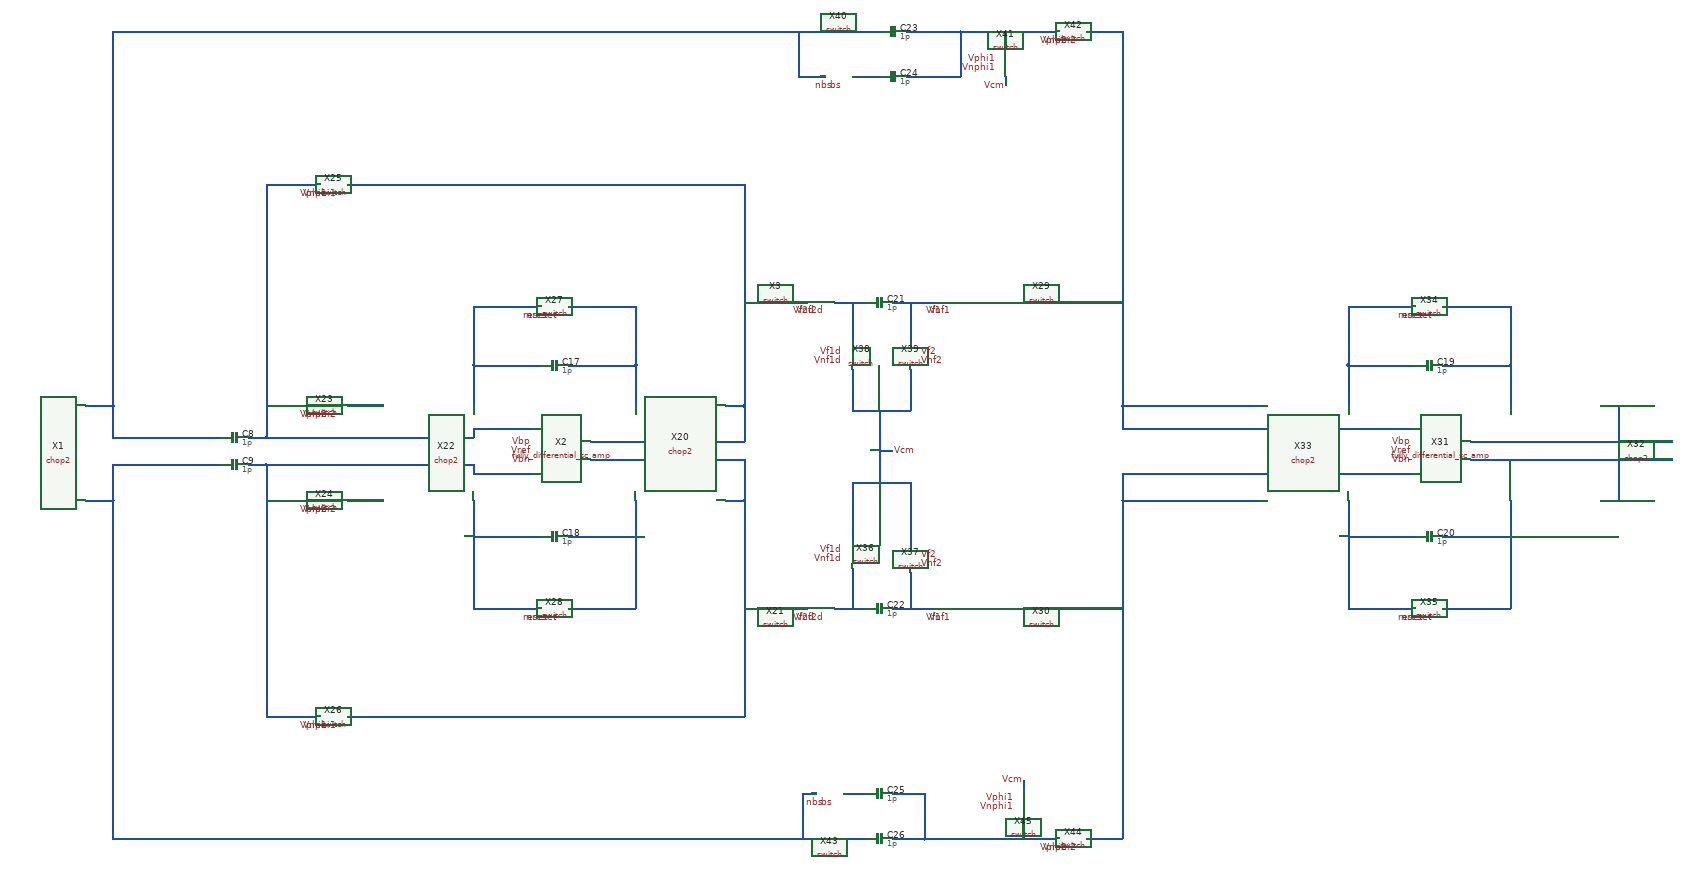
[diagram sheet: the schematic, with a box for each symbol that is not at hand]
v {xschem version=2.9.9 file_version=1.2 }
G {}
K {}
V {}
S {}
E {}
N 840 -1180 840 -620 { lab=#net1}
N 840 -560 840 -0 { lab=#net2}
N 840 -1180 960 -1180 { lab=#net1}
N 840 -690 960 -690 { lab=#net1}
N 1020 -690 1100 -690 { lab=#net3}
N 840 0 960 -0 { lab=#net2}
N 1300 -780 1450 -780 { lab=#net4}
N 1510 -780 1660 -780 { lab=#net5}
N 1660 -780 1660 -690 { lab=#net5}
N 1300 -400 1450 -400 { lab=#net6}
N 1510 -400 1660 -400 { lab=#net7}
N 1660 -480 1660 -420 { lab=#net7}
N 1300 -910 1450 -910 { lab=#net4}
N 1300 -910 1300 -780 { lab=#net4}
N 1510 -910 1660 -910 { lab=#net5}
N 1660 -910 1660 -780 { lab=#net5}
N 1510 -240 1660 -240 { lab=#net7}
N 1660 -420 1660 -240 { lab=#net7}
N 1300 -420 1300 -240 { lab=#net6}
N 1300 -240 1450 -240 { lab=#net6}
N 1300 -780 1300 -690 { lab=#net4}
N 1300 -480 1300 -420 { lab=#net6}
N 840 -480 960 -480 { lab=#net2}
N 1020 -480 1100 -480 { lab=#net8}
N 1860 -690 1900 -690 { lab=#net9}
N 1900 -1180 1900 -690 { lab=#net9}
N 1020 -1180 1900 -1180 { lab=#net9}
N 1020 -0 1900 -0 { lab=#net10}
N 1900 -480 1900 -0 { lab=#net10}
N 1860 -480 1900 -480 { lab=#net10}
N 3240 -780 3390 -780 { lab=#net11}
N 3450 -780 3600 -780 { lab=#net12}
N 3600 -780 3600 -690 { lab=#net12}
N 3240 -400 3390 -400 { lab=#net13}
N 3450 -400 3600 -400 { lab=#net14}
N 3600 -480 3600 -420 { lab=#net14}
N 3240 -910 3390 -910 { lab=#net11}
N 3240 -910 3240 -780 { lab=#net11}
N 3450 -910 3600 -910 { lab=#net12}
N 3600 -910 3600 -780 { lab=#net12}
N 3450 -240 3600 -240 { lab=#net14}
N 3600 -420 3600 -240 { lab=#net14}
N 3240 -420 3240 -240 { lab=#net13}
N 3240 -240 3390 -240 { lab=#net13}
N 3240 -780 3240 -690 { lab=#net11}
N 3240 -480 3240 -420 { lab=#net13}
N 500 270 2170 270 { lab=#net15}
N 2030 170 2060 170 { lab=#net15}
N 2030 170 2030 270 { lab=#net15}
N 2120 170 2170 170 { lab=#net16}
N 2230 170 2300 170 { lab=#net17}
N 2300 170 2300 270 { lab=#net17}
N 2230 270 2300 270 { lab=#net17}
N 2300 270 2600 270 { lab=#net17}
N 2520 220 2520 270 { lab=#net17}
N 1900 -240 2040 -240 { lab=#net10}
N 2100 -240 2170 -240 { lab=#net18}
N 2140 -330 2140 -240 { lab=#net18}
N 2230 -240 2320 -240 { lab=#net19}
N 2270 -320 2270 -240 { lab=#net19}
N 1900 -920 2040 -920 { lab=#net9}
N 2100 -920 2170 -920 { lab=#net20}
N 2140 -920 2140 -830 { lab=#net20}
N 2230 -920 2320 -920 { lab=#net21}
N 2140 -520 2140 -390 { lab=Vcm}
N 2270 -520 2270 -380 { lab=Vcm}
N 2140 -520 2270 -520 { lab=Vcm}
N 2140 -770 2140 -680 { lab=Vcm}
N 2140 -680 2270 -680 { lab=Vcm}
N 2270 -770 2270 -680 { lab=Vcm}
N 2270 -920 2270 -830 { lab=#net21}
N 2200 -680 2200 -520 { lab=Vcm}
N 500 -1520 2200 -1520 { lab=#net22}
N 2020 -1420 2080 -1420 { lab=#net22}
N 2020 -1520 2020 -1420 { lab=#net22}
N 2140 -1420 2200 -1420 { lab=#net23}
N 2260 -1520 2380 -1520 { lab=#net24}
N 2380 -1520 2380 -1420 { lab=#net24}
N 2260 -1420 2380 -1420 { lab=#net24}
N 2480 -1520 2480 -1480 { lab=#net24}
N 2660 -1520 2740 -1520 { lab=#net25}
N 2660 270 2740 270 { lab=#net26}
N 2740 -480 2740 270 { lab=#net26}
N 2740 -480 3040 -480 { lab=#net26}
N 2380 -240 2740 -240 { lab=#net26}
N 2740 -690 3040 -690 { lab=#net25}
N 2740 -1520 2740 -690 { lab=#net25}
N 2380 -1520 2600 -1520 { lab=#net24}
N 2380 -920 2740 -920 { lab=#net25}
N 3800 -480 3840 -480 { lab=#net27}
N 3800 -690 3840 -690 { lab=#net28}
N 800 -560 840 -560 { lab=#net2}
N 800 -620 840 -620 { lab=#net1}
N 840 -620 1300 -620 { lab=#net1}
N 840 -560 1300 -560 { lab=#net2}
N 1560 -570 1900 -570 { lab=#net10}
N 1900 -570 1900 -480 { lab=#net10}
N 1560 -610 1900 -610 { lab=#net9}
N 1900 -690 1900 -610 { lab=#net9}
N 3510 -570 3960 -570 { lab=#net27}
N 3510 -610 3960 -610 { lab=#net28}
N 3840 -690 3840 -610 { lab=#net28}
N 3840 -570 3840 -480 { lab=#net27}
N 1300 -640 1430 -640 { lab=#net1}
N 1300 -640 1300 -620 { lab=#net1}
N 1300 -540 1430 -540 { lab=#net2}
N 1300 -560 1300 -540 { lab=#net2}
N 2740 -540 3380 -540 { lab=#net26}
N 2740 -540 2740 -480 { lab=#net26}
N 2740 -640 3380 -640 { lab=#net25}
N 2740 -690 2740 -640 { lab=#net25}
N 500 -1520 500 -690 { lab=#net22}
N 440 -690 500 -690 { lab=#net22}
N 500 -690 500 -620 { lab=#net22}
N 500 -480 500 270 { lab=#net15}
N 440 -480 500 -480 { lab=#net15}
N 500 -560 500 -480 { lab=#net15}
N 500 -620 740 -620 { lab=#net22}
N 500 -560 740 -560 { lab=#net15}
N 2520 140 2520 160 { lab=Vcm}
N 2480 -1420 2480 -1400 { lab=Vcm}
N 2200 -590 2230 -590 { lab=Vcm}
C {/home/madvlsi/Documents/MADVLSI-Final_Project/schematic/chop2.sym} 340 -590 0 0 {name=X1 Wp=1 Lp=0.15 WW=1 LL=0.15}
C {madvlsi/capacitor.sym} 770 -620 1 0 {name=C8
value=1p
m=1}
C {madvlsi/capacitor.sym} 770 -560 1 0 {name=C9
value=1p
m=1}
C {madvlsi/capacitor.sym} 1480 -780 1 0 {name=C17
value=1p
m=1}
C {madvlsi/capacitor.sym} 1480 -400 1 0 {name=C18
value=1p
m=1}
C {/home/madvlsi/Documents/MADVLSI-Final_Project/schematic/chop2.sym} 1760 -590 0 0 {name=X20 Wp=1 Lp=0.15 WW=1 LL=0.15}
C {/home/madvlsi/Documents/MADVLSI-Final_Project/schematic/chop2.sym} 1200 -590 0 0 {name=X22 Wp=1 Lp=0.15 WW=1 LL=0.15}
C {/home/madvlsi/Documents/MADVLSI-Final_Project/schematic/switch.sym} 990 -690 0 0 {name=X23 Wp=1 Lp=0.15 WW=1 LL=0.15}
C {/home/madvlsi/Documents/MADVLSI-Final_Project/schematic/switch.sym} 990 -480 0 0 {name=X24 Wp=1 Lp=0.15 WW=1 LL=0.15}
C {/home/madvlsi/Documents/MADVLSI-Final_Project/schematic/switch.sym} 990 -1180 0 0 {name=X25 Wp=1 Lp=0.15 WW=1 LL=0.15}
C {/home/madvlsi/Documents/MADVLSI-Final_Project/schematic/switch.sym} 990 0 0 0 {name=X26 Wp=1 Lp=0.15 WW=1 LL=0.15}
C {/home/madvlsi/Documents/MADVLSI-Final_Project/schematic/switch.sym} 1480 -910 0 0 {name=X27 Wp=1 Lp=0.15 WW=1 LL=0.15}
C {/home/madvlsi/Documents/MADVLSI-Final_Project/schematic/switch.sym} 1480 -240 0 0 {name=X28 Wp=1 Lp=0.15 WW=1 LL=0.15}
C {/home/madvlsi/Documents/MADVLSI-Final_Project/schematic/switch.sym} 2070 -920 0 0 {name=X3 Wp=1 Lp=0.15 WW=1 LL=0.15}
C {/home/madvlsi/Documents/MADVLSI-Final_Project/schematic/switch.sym} 2070 -240 0 0 {name=X21 Wp=1 Lp=0.15 WW=1 LL=0.15}
C {/home/madvlsi/Documents/MADVLSI-Final_Project/schematic/switch.sym} 2350 -920 0 0 {name=X29 Wp=1 Lp=0.15 WW=1 LL=0.15}
C {/home/madvlsi/Documents/MADVLSI-Final_Project/schematic/switch.sym} 2350 -240 0 0 {name=X30 Wp=1 Lp=0.15 WW=1 LL=0.15}
C {madvlsi/capacitor.sym} 3420 -780 1 0 {name=C19
value=1p
m=1}
C {madvlsi/capacitor.sym} 3420 -400 1 0 {name=C20
value=1p
m=1}
C {/home/madvlsi/Documents/MADVLSI-Final_Project/schematic/chop2.sym} 3700 -590 0 0 {name=X32 Wp=1 Lp=0.15 WW=1 LL=0.15}
C {/home/madvlsi/Documents/MADVLSI-Final_Project/schematic/chop2.sym} 3140 -590 0 0 {name=X33 Wp=1 Lp=0.15 WW=1 LL=0.15}
C {/home/madvlsi/Documents/MADVLSI-Final_Project/schematic/switch.sym} 3420 -910 0 0 {name=X34 Wp=1 Lp=0.15 WW=1 LL=0.15}
C {/home/madvlsi/Documents/MADVLSI-Final_Project/schematic/switch.sym} 3420 -240 0 0 {name=X35 Wp=1 Lp=0.15 WW=1 LL=0.15}
C {madvlsi/capacitor.sym} 2200 -920 1 0 {name=C21
value=1p
m=1}
C {madvlsi/capacitor.sym} 2200 -240 1 0 {name=C22
value=1p
m=1}
C {/home/madvlsi/Documents/MADVLSI-Final_Project/schematic/switch.sym} 2140 -360 1 0 {name=X36 Wp=1 Lp=0.15 WW=1 LL=0.15}
C {/home/madvlsi/Documents/MADVLSI-Final_Project/schematic/switch.sym} 2270 -350 3 0 {name=X37 Wp=1 Lp=0.15 WW=1 LL=0.15}
C {/home/madvlsi/Documents/MADVLSI-Final_Project/schematic/switch.sym} 2140 -800 1 0 {name=X38 Wp=1 Lp=0.15 WW=1 LL=0.15}
C {/home/madvlsi/Documents/MADVLSI-Final_Project/schematic/switch.sym} 2270 -800 3 0 {name=X39 Wp=1 Lp=0.15 WW=1 LL=0.15}
C {madvlsi/capacitor.sym} 2230 -1520 1 0 {name=C23
value=1p
m=1}
C {madvlsi/capacitor.sym} 2230 -1420 1 0 {name=C24
value=1p
m=1}
C {/home/madvlsi/Documents/MADVLSI-Final_Project/schematic/switch.sym} 2110 -1420 0 0 {name=X40 Wp=1 Lp=0.15 WW=1 LL=0.15}
C {/home/madvlsi/Documents/MADVLSI-Final_Project/schematic/switch.sym} 2480 -1450 1 0 {name=X41 Wp=1 Lp=0.15 WW=1 LL=0.15}
C {/home/madvlsi/Documents/MADVLSI-Final_Project/schematic/switch.sym} 2630 -1520 0 0 {name=X42 Wp=1 Lp=0.15 WW=1 LL=0.15}
C {madvlsi/capacitor.sym} 2200 170 1 0 {name=C25
value=1p
m=1}
C {madvlsi/capacitor.sym} 2200 270 1 0 {name=C26
value=1p
m=1}
C {/home/madvlsi/Documents/MADVLSI-Final_Project/schematic/switch.sym} 2090 170 0 0 {name=X43 Wp=1 Lp=0.15 WW=1 LL=0.15}
C {/home/madvlsi/Documents/MADVLSI-Final_Project/schematic/switch.sym} 2630 270 0 0 {name=X44 Wp=1 Lp=0.15 WW=1 LL=0.15}
C {/home/madvlsi/Documents/MADVLSI-Final_Project/schematic/switch.sym} 2520 190 1 0 {name=X45 Wp=1 Lp=0.15 WW=1 LL=0.15}
C {/home/madvlsi/Documents/MADVLSI-Final_Project/schematic/fully_differential_sc_amp.sym} 1540 -630 0 0 {name=X2 Wp=1 Lp=0.15 WW=1 LL=0.15}
C {/home/madvlsi/Documents/MADVLSI-Final_Project/schematic/fully_differential_sc_amp.sym} 3490 -630 0 0 {name=X31 Wp=1 Lp=0.15 WW=1 LL=0.15}
C {devices/lab_pin.sym} 980 -670 3 0 {name=l3 sig_type=std_logic lab=Vphi2}
C {devices/lab_pin.sym} 1000 -670 3 0 {name=l4 sig_type=std_logic lab=Vnphi2}
C {devices/lab_pin.sym} 980 -460 3 0 {name=l5 sig_type=std_logic lab=Vphi2}
C {devices/lab_pin.sym} 1000 -460 3 0 {name=l6 sig_type=std_logic lab=Vnphi2}
C {devices/lab_pin.sym} 980 -1160 3 0 {name=l7 sig_type=std_logic lab=Vphi1}
C {devices/lab_pin.sym} 1000 -1160 3 0 {name=l8 sig_type=std_logic lab=Vnphi1}
C {devices/lab_pin.sym} 980 20 3 0 {name=l9 sig_type=std_logic lab=Vphi1}
C {devices/lab_pin.sym} 1000 20 3 0 {name=l10 sig_type=std_logic lab=Vnphi1}
C {devices/lab_pin.sym} 1470 -890 3 0 {name=l11 sig_type=std_logic lab=reset}
C {devices/lab_pin.sym} 1490 -890 3 0 {name=l12 sig_type=std_logic lab=nreset}
C {devices/lab_pin.sym} 1470 -220 3 0 {name=l13 sig_type=std_logic lab=reset}
C {devices/lab_pin.sym} 1490 -220 3 0 {name=l14 sig_type=std_logic lab=nreset}
C {devices/lab_pin.sym} 2060 -900 3 0 {name=l1 sig_type=std_logic lab=Vf2d}
C {devices/lab_pin.sym} 2080 -900 3 0 {name=l2 sig_type=std_logic lab=Vnf2d}
C {devices/lab_pin.sym} 2100 -1400 3 0 {name=l15 sig_type=std_logic lab=nbs}
C {devices/lab_pin.sym} 2120 -1400 3 0 {name=l16 sig_type=std_logic lab=bs}
C {devices/lab_pin.sym} 2080 190 3 0 {name=l17 sig_type=std_logic lab=nbs}
C {devices/lab_pin.sym} 2100 190 3 0 {name=l18 sig_type=std_logic lab=bs}
C {devices/lab_pin.sym} 2520 140 1 0 {name=l19 sig_type=std_logic lab=Vcm}
C {devices/lab_pin.sym} 2480 -1400 3 0 {name=l20 sig_type=std_logic lab=Vcm}
C {devices/lab_pin.sym} 2500 180 0 0 {name=l21 sig_type=std_logic lab=Vphi1}
C {devices/lab_pin.sym} 2500 200 0 0 {name=l22 sig_type=std_logic lab=Vnphi1}
C {devices/lab_pin.sym} 2460 -1460 0 0 {name=l23 sig_type=std_logic lab=Vphi1}
C {devices/lab_pin.sym} 2460 -1440 0 0 {name=l24 sig_type=std_logic lab=Vnphi1}
C {devices/lab_pin.sym} 2620 290 3 0 {name=l25 sig_type=std_logic lab=Vphi2}
C {devices/lab_pin.sym} 2640 290 3 0 {name=l26 sig_type=std_logic lab=Vnphi2}
C {devices/lab_pin.sym} 2620 -1500 3 0 {name=l27 sig_type=std_logic lab=Vphi2}
C {devices/lab_pin.sym} 2640 -1500 3 0 {name=l28 sig_type=std_logic lab=Vnphi2}
C {devices/lab_pin.sym} 2230 -590 2 0 {name=l29 sig_type=std_logic lab=Vcm}
C {devices/lab_pin.sym} 2060 -220 3 0 {name=l30 sig_type=std_logic lab=Vf2d}
C {devices/lab_pin.sym} 2080 -220 3 0 {name=l31 sig_type=std_logic lab=Vnf2d}
C {devices/lab_pin.sym} 2340 -220 3 0 {name=l32 sig_type=std_logic lab=Vf1}
C {devices/lab_pin.sym} 2360 -220 3 0 {name=l33 sig_type=std_logic lab=Vnf1}
C {devices/lab_pin.sym} 2120 -810 0 0 {name=l34 sig_type=std_logic lab=Vf1d}
C {devices/lab_pin.sym} 2120 -790 0 0 {name=l35 sig_type=std_logic lab=Vnf1d}
C {devices/lab_pin.sym} 2340 -900 3 0 {name=l36 sig_type=std_logic lab=Vf1}
C {devices/lab_pin.sym} 2360 -900 3 0 {name=l37 sig_type=std_logic lab=Vnf1}
C {devices/lab_pin.sym} 2120 -370 0 0 {name=l38 sig_type=std_logic lab=Vf1d}
C {devices/lab_pin.sym} 2120 -350 0 0 {name=l39 sig_type=std_logic lab=Vnf1d}
C {devices/lab_pin.sym} 2290 -810 2 0 {name=l40 sig_type=std_logic lab=Vf2}
C {devices/lab_pin.sym} 2290 -790 2 0 {name=l41 sig_type=std_logic lab=Vnf2}
C {devices/lab_pin.sym} 2290 -360 2 0 {name=l42 sig_type=std_logic lab=Vf2}
C {devices/lab_pin.sym} 2290 -340 2 0 {name=l43 sig_type=std_logic lab=Vnf2}
C {devices/lab_pin.sym} 3410 -890 3 0 {name=l44 sig_type=std_logic lab=reset}
C {devices/lab_pin.sym} 3430 -890 3 0 {name=l45 sig_type=std_logic lab=nreset}
C {devices/lab_pin.sym} 3410 -220 3 0 {name=l46 sig_type=std_logic lab=reset}
C {devices/lab_pin.sym} 3430 -220 3 0 {name=l47 sig_type=std_logic lab=nreset}
C {devices/lab_pin.sym} 1430 -610 0 0 {name=l48 sig_type=std_logic lab=Vbp}
C {devices/lab_pin.sym} 1430 -590 0 0 {name=l49 sig_type=std_logic lab=Vref}
C {devices/lab_pin.sym} 1430 -570 0 0 {name=l50 sig_type=std_logic lab=Vbn}
C {devices/lab_pin.sym} 3380 -610 0 0 {name=l51 sig_type=std_logic lab=Vbp}
C {devices/lab_pin.sym} 3380 -590 0 0 {name=l52 sig_type=std_logic lab=Vref}
C {devices/lab_pin.sym} 3380 -570 0 0 {name=l53 sig_type=std_logic lab=Vbn}
